VERSION 5.7 ;
  NOWIREEXTENSIONATPIN ON ;
  DIVIDERCHAR "/" ;
  BUSBITCHARS "[]" ;
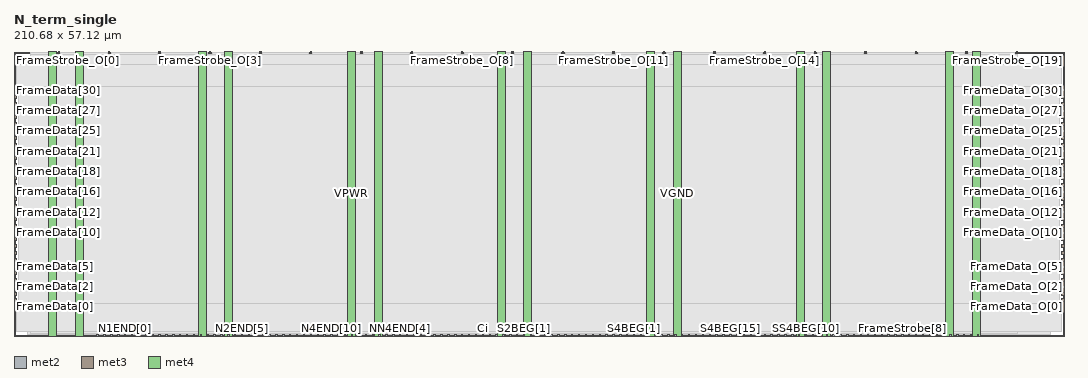
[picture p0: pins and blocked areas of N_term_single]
MACRO N_term_single
  CLASS BLOCK ;
  FOREIGN N_term_single ;
  ORIGIN 0.000 0.000 ;
  SIZE 210.680 BY 57.120 ;
  PIN Ci
    DIRECTION INPUT ;
    USE SIGNAL ;
    PORT
      LAYER met2 ;
        RECT 93.930 0.000 94.210 0.280 ;
    END
  END Ci
  PIN FrameData[0]
    DIRECTION INPUT ;
    USE SIGNAL ;
    ANTENNAGATEAREA 0.159000 ;
    PORT
      LAYER met3 ;
        RECT 0.000 6.840 0.600 7.440 ;
    END
  END FrameData[0]
  PIN FrameData[10]
    DIRECTION INPUT ;
    USE SIGNAL ;
    ANTENNAGATEAREA 0.593700 ;
    ANTENNADIFFAREA 0.434700 ;
    PORT
      LAYER met3 ;
        RECT 0.000 20.440 0.600 21.040 ;
    END
  END FrameData[10]
  PIN FrameData[11]
    DIRECTION INPUT ;
    USE SIGNAL ;
    ANTENNAGATEAREA 0.593700 ;
    ANTENNADIFFAREA 0.434700 ;
    PORT
      LAYER met3 ;
        RECT 0.000 21.800 0.600 22.400 ;
    END
  END FrameData[11]
  PIN FrameData[12]
    DIRECTION INPUT ;
    USE SIGNAL ;
    ANTENNAGATEAREA 0.593700 ;
    ANTENNADIFFAREA 0.434700 ;
    PORT
      LAYER met3 ;
        RECT 0.000 23.160 0.600 23.760 ;
    END
  END FrameData[12]
  PIN FrameData[13]
    DIRECTION INPUT ;
    USE SIGNAL ;
    ANTENNAGATEAREA 0.593700 ;
    ANTENNADIFFAREA 0.434700 ;
    PORT
      LAYER met3 ;
        RECT 0.000 24.520 0.600 25.120 ;
    END
  END FrameData[13]
  PIN FrameData[14]
    DIRECTION INPUT ;
    USE SIGNAL ;
    ANTENNAGATEAREA 0.593700 ;
    ANTENNADIFFAREA 0.434700 ;
    PORT
      LAYER met3 ;
        RECT 0.000 25.880 0.600 26.480 ;
    END
  END FrameData[14]
  PIN FrameData[15]
    DIRECTION INPUT ;
    USE SIGNAL ;
    ANTENNAGATEAREA 0.159000 ;
    PORT
      LAYER met3 ;
        RECT 0.000 27.240 0.600 27.840 ;
    END
  END FrameData[15]
  PIN FrameData[16]
    DIRECTION INPUT ;
    USE SIGNAL ;
    ANTENNAGATEAREA 0.593700 ;
    ANTENNADIFFAREA 0.434700 ;
    PORT
      LAYER met3 ;
        RECT 0.000 28.600 0.600 29.200 ;
    END
  END FrameData[16]
  PIN FrameData[17]
    DIRECTION INPUT ;
    USE SIGNAL ;
    ANTENNAGATEAREA 0.593700 ;
    ANTENNADIFFAREA 0.434700 ;
    PORT
      LAYER met3 ;
        RECT 0.000 29.960 0.600 30.560 ;
    END
  END FrameData[17]
  PIN FrameData[18]
    DIRECTION INPUT ;
    USE SIGNAL ;
    ANTENNAGATEAREA 0.593700 ;
    ANTENNADIFFAREA 0.434700 ;
    PORT
      LAYER met3 ;
        RECT 0.000 31.320 0.600 31.920 ;
    END
  END FrameData[18]
  PIN FrameData[19]
    DIRECTION INPUT ;
    USE SIGNAL ;
    ANTENNAGATEAREA 0.593700 ;
    ANTENNADIFFAREA 0.434700 ;
    PORT
      LAYER met3 ;
        RECT 0.000 32.680 0.600 33.280 ;
    END
  END FrameData[19]
  PIN FrameData[1]
    DIRECTION INPUT ;
    USE SIGNAL ;
    ANTENNAGATEAREA 0.593700 ;
    ANTENNADIFFAREA 0.434700 ;
    PORT
      LAYER met3 ;
        RECT 0.000 8.200 0.600 8.800 ;
    END
  END FrameData[1]
  PIN FrameData[20]
    DIRECTION INPUT ;
    USE SIGNAL ;
    ANTENNAGATEAREA 0.593700 ;
    ANTENNADIFFAREA 0.434700 ;
    PORT
      LAYER met3 ;
        RECT 0.000 34.040 0.600 34.640 ;
    END
  END FrameData[20]
  PIN FrameData[21]
    DIRECTION INPUT ;
    USE SIGNAL ;
    ANTENNAGATEAREA 0.593700 ;
    ANTENNADIFFAREA 0.434700 ;
    PORT
      LAYER met3 ;
        RECT 0.000 35.400 0.600 36.000 ;
    END
  END FrameData[21]
  PIN FrameData[22]
    DIRECTION INPUT ;
    USE SIGNAL ;
    ANTENNAGATEAREA 0.159000 ;
    PORT
      LAYER met3 ;
        RECT 0.000 36.760 0.600 37.360 ;
    END
  END FrameData[22]
  PIN FrameData[23]
    DIRECTION INPUT ;
    USE SIGNAL ;
    ANTENNAGATEAREA 0.593700 ;
    ANTENNADIFFAREA 0.434700 ;
    PORT
      LAYER met3 ;
        RECT 0.000 38.120 0.600 38.720 ;
    END
  END FrameData[23]
  PIN FrameData[24]
    DIRECTION INPUT ;
    USE SIGNAL ;
    ANTENNAGATEAREA 0.593700 ;
    ANTENNADIFFAREA 0.434700 ;
    PORT
      LAYER met3 ;
        RECT 0.000 39.480 0.600 40.080 ;
    END
  END FrameData[24]
  PIN FrameData[25]
    DIRECTION INPUT ;
    USE SIGNAL ;
    ANTENNAGATEAREA 0.593700 ;
    ANTENNADIFFAREA 0.434700 ;
    PORT
      LAYER met3 ;
        RECT 0.000 40.840 0.600 41.440 ;
    END
  END FrameData[25]
  PIN FrameData[26]
    DIRECTION INPUT ;
    USE SIGNAL ;
    ANTENNAGATEAREA 0.593700 ;
    ANTENNADIFFAREA 0.434700 ;
    PORT
      LAYER met3 ;
        RECT 0.000 42.200 0.600 42.800 ;
    END
  END FrameData[26]
  PIN FrameData[27]
    DIRECTION INPUT ;
    USE SIGNAL ;
    ANTENNAGATEAREA 0.593700 ;
    ANTENNADIFFAREA 0.434700 ;
    PORT
      LAYER met3 ;
        RECT 0.000 43.560 0.600 44.160 ;
    END
  END FrameData[27]
  PIN FrameData[28]
    DIRECTION INPUT ;
    USE SIGNAL ;
    ANTENNAGATEAREA 0.593700 ;
    ANTENNADIFFAREA 0.434700 ;
    PORT
      LAYER met3 ;
        RECT 0.000 44.920 0.600 45.520 ;
    END
  END FrameData[28]
  PIN FrameData[29]
    DIRECTION INPUT ;
    USE SIGNAL ;
    ANTENNAGATEAREA 0.593700 ;
    ANTENNADIFFAREA 0.434700 ;
    PORT
      LAYER met3 ;
        RECT 0.000 46.280 0.600 46.880 ;
    END
  END FrameData[29]
  PIN FrameData[2]
    DIRECTION INPUT ;
    USE SIGNAL ;
    ANTENNAGATEAREA 0.593700 ;
    ANTENNADIFFAREA 0.434700 ;
    PORT
      LAYER met3 ;
        RECT 0.000 9.560 0.600 10.160 ;
    END
  END FrameData[2]
  PIN FrameData[30]
    DIRECTION INPUT ;
    USE SIGNAL ;
    ANTENNAGATEAREA 0.593700 ;
    ANTENNADIFFAREA 0.434700 ;
    PORT
      LAYER met3 ;
        RECT 0.000 47.640 0.600 48.240 ;
    END
  END FrameData[30]
  PIN FrameData[31]
    DIRECTION INPUT ;
    USE SIGNAL ;
    ANTENNAGATEAREA 0.593700 ;
    ANTENNADIFFAREA 0.434700 ;
    PORT
      LAYER met3 ;
        RECT 0.000 49.000 0.600 49.600 ;
    END
  END FrameData[31]
  PIN FrameData[3]
    DIRECTION INPUT ;
    USE SIGNAL ;
    ANTENNAGATEAREA 0.159000 ;
    PORT
      LAYER met3 ;
        RECT 0.000 10.920 0.600 11.520 ;
    END
  END FrameData[3]
  PIN FrameData[4]
    DIRECTION INPUT ;
    USE SIGNAL ;
    ANTENNAGATEAREA 0.593700 ;
    ANTENNADIFFAREA 0.434700 ;
    PORT
      LAYER met3 ;
        RECT 0.000 12.280 0.600 12.880 ;
    END
  END FrameData[4]
  PIN FrameData[5]
    DIRECTION INPUT ;
    USE SIGNAL ;
    ANTENNAGATEAREA 0.593700 ;
    ANTENNADIFFAREA 0.434700 ;
    PORT
      LAYER met3 ;
        RECT 0.000 13.640 0.600 14.240 ;
    END
  END FrameData[5]
  PIN FrameData[6]
    DIRECTION INPUT ;
    USE SIGNAL ;
    ANTENNAGATEAREA 0.593700 ;
    ANTENNADIFFAREA 0.434700 ;
    PORT
      LAYER met3 ;
        RECT 0.000 15.000 0.600 15.600 ;
    END
  END FrameData[6]
  PIN FrameData[7]
    DIRECTION INPUT ;
    USE SIGNAL ;
    ANTENNAGATEAREA 0.593700 ;
    ANTENNADIFFAREA 0.434700 ;
    PORT
      LAYER met3 ;
        RECT 0.000 16.360 0.600 16.960 ;
    END
  END FrameData[7]
  PIN FrameData[8]
    DIRECTION INPUT ;
    USE SIGNAL ;
    ANTENNAGATEAREA 0.593700 ;
    ANTENNADIFFAREA 0.434700 ;
    PORT
      LAYER met3 ;
        RECT 0.000 17.720 0.600 18.320 ;
    END
  END FrameData[8]
  PIN FrameData[9]
    DIRECTION INPUT ;
    USE SIGNAL ;
    ANTENNAGATEAREA 0.593700 ;
    ANTENNADIFFAREA 0.434700 ;
    PORT
      LAYER met3 ;
        RECT 0.000 19.080 0.600 19.680 ;
    END
  END FrameData[9]
  PIN FrameData_O[0]
    DIRECTION OUTPUT ;
    USE SIGNAL ;
    ANTENNADIFFAREA 0.702900 ;
    PORT
      LAYER met3 ;
        RECT 210.080 6.840 210.680 7.440 ;
    END
  END FrameData_O[0]
  PIN FrameData_O[10]
    DIRECTION OUTPUT ;
    USE SIGNAL ;
    ANTENNADIFFAREA 0.702900 ;
    PORT
      LAYER met3 ;
        RECT 210.080 20.440 210.680 21.040 ;
    END
  END FrameData_O[10]
  PIN FrameData_O[11]
    DIRECTION OUTPUT ;
    USE SIGNAL ;
    ANTENNADIFFAREA 0.702900 ;
    PORT
      LAYER met3 ;
        RECT 210.080 21.800 210.680 22.400 ;
    END
  END FrameData_O[11]
  PIN FrameData_O[12]
    DIRECTION OUTPUT ;
    USE SIGNAL ;
    ANTENNADIFFAREA 0.702900 ;
    PORT
      LAYER met3 ;
        RECT 210.080 23.160 210.680 23.760 ;
    END
  END FrameData_O[12]
  PIN FrameData_O[13]
    DIRECTION OUTPUT ;
    USE SIGNAL ;
    ANTENNADIFFAREA 0.702900 ;
    PORT
      LAYER met3 ;
        RECT 210.080 24.520 210.680 25.120 ;
    END
  END FrameData_O[13]
  PIN FrameData_O[14]
    DIRECTION OUTPUT ;
    USE SIGNAL ;
    ANTENNADIFFAREA 0.702900 ;
    PORT
      LAYER met3 ;
        RECT 210.080 25.880 210.680 26.480 ;
    END
  END FrameData_O[14]
  PIN FrameData_O[15]
    DIRECTION OUTPUT ;
    USE SIGNAL ;
    ANTENNADIFFAREA 0.702900 ;
    PORT
      LAYER met3 ;
        RECT 210.080 27.240 210.680 27.840 ;
    END
  END FrameData_O[15]
  PIN FrameData_O[16]
    DIRECTION OUTPUT ;
    USE SIGNAL ;
    ANTENNADIFFAREA 0.702900 ;
    PORT
      LAYER met3 ;
        RECT 210.080 28.600 210.680 29.200 ;
    END
  END FrameData_O[16]
  PIN FrameData_O[17]
    DIRECTION OUTPUT ;
    USE SIGNAL ;
    ANTENNADIFFAREA 0.702900 ;
    PORT
      LAYER met3 ;
        RECT 210.080 29.960 210.680 30.560 ;
    END
  END FrameData_O[17]
  PIN FrameData_O[18]
    DIRECTION OUTPUT ;
    USE SIGNAL ;
    ANTENNADIFFAREA 0.702900 ;
    PORT
      LAYER met3 ;
        RECT 210.080 31.320 210.680 31.920 ;
    END
  END FrameData_O[18]
  PIN FrameData_O[19]
    DIRECTION OUTPUT ;
    USE SIGNAL ;
    ANTENNADIFFAREA 0.702900 ;
    PORT
      LAYER met3 ;
        RECT 210.080 32.680 210.680 33.280 ;
    END
  END FrameData_O[19]
  PIN FrameData_O[1]
    DIRECTION OUTPUT ;
    USE SIGNAL ;
    ANTENNADIFFAREA 0.702900 ;
    PORT
      LAYER met3 ;
        RECT 210.080 8.200 210.680 8.800 ;
    END
  END FrameData_O[1]
  PIN FrameData_O[20]
    DIRECTION OUTPUT ;
    USE SIGNAL ;
    ANTENNADIFFAREA 0.702900 ;
    PORT
      LAYER met3 ;
        RECT 210.080 34.040 210.680 34.640 ;
    END
  END FrameData_O[20]
  PIN FrameData_O[21]
    DIRECTION OUTPUT ;
    USE SIGNAL ;
    ANTENNADIFFAREA 0.702900 ;
    PORT
      LAYER met3 ;
        RECT 210.080 35.400 210.680 36.000 ;
    END
  END FrameData_O[21]
  PIN FrameData_O[22]
    DIRECTION OUTPUT ;
    USE SIGNAL ;
    ANTENNADIFFAREA 0.702900 ;
    PORT
      LAYER met3 ;
        RECT 210.080 36.760 210.680 37.360 ;
    END
  END FrameData_O[22]
  PIN FrameData_O[23]
    DIRECTION OUTPUT ;
    USE SIGNAL ;
    ANTENNADIFFAREA 0.702900 ;
    PORT
      LAYER met3 ;
        RECT 210.080 38.120 210.680 38.720 ;
    END
  END FrameData_O[23]
  PIN FrameData_O[24]
    DIRECTION OUTPUT ;
    USE SIGNAL ;
    ANTENNADIFFAREA 0.702900 ;
    PORT
      LAYER met3 ;
        RECT 210.080 39.480 210.680 40.080 ;
    END
  END FrameData_O[24]
  PIN FrameData_O[25]
    DIRECTION OUTPUT ;
    USE SIGNAL ;
    ANTENNADIFFAREA 0.702900 ;
    PORT
      LAYER met3 ;
        RECT 210.080 40.840 210.680 41.440 ;
    END
  END FrameData_O[25]
  PIN FrameData_O[26]
    DIRECTION OUTPUT ;
    USE SIGNAL ;
    ANTENNADIFFAREA 0.702900 ;
    PORT
      LAYER met3 ;
        RECT 210.080 42.200 210.680 42.800 ;
    END
  END FrameData_O[26]
  PIN FrameData_O[27]
    DIRECTION OUTPUT ;
    USE SIGNAL ;
    ANTENNADIFFAREA 0.702900 ;
    PORT
      LAYER met3 ;
        RECT 210.080 43.560 210.680 44.160 ;
    END
  END FrameData_O[27]
  PIN FrameData_O[28]
    DIRECTION OUTPUT ;
    USE SIGNAL ;
    ANTENNADIFFAREA 0.702900 ;
    PORT
      LAYER met3 ;
        RECT 210.080 44.920 210.680 45.520 ;
    END
  END FrameData_O[28]
  PIN FrameData_O[29]
    DIRECTION OUTPUT ;
    USE SIGNAL ;
    ANTENNADIFFAREA 0.702900 ;
    PORT
      LAYER met3 ;
        RECT 210.080 46.280 210.680 46.880 ;
    END
  END FrameData_O[29]
  PIN FrameData_O[2]
    DIRECTION OUTPUT ;
    USE SIGNAL ;
    ANTENNADIFFAREA 0.702900 ;
    PORT
      LAYER met3 ;
        RECT 210.080 9.560 210.680 10.160 ;
    END
  END FrameData_O[2]
  PIN FrameData_O[30]
    DIRECTION OUTPUT ;
    USE SIGNAL ;
    ANTENNADIFFAREA 0.702900 ;
    PORT
      LAYER met3 ;
        RECT 210.080 47.640 210.680 48.240 ;
    END
  END FrameData_O[30]
  PIN FrameData_O[31]
    DIRECTION OUTPUT ;
    USE SIGNAL ;
    ANTENNADIFFAREA 0.702900 ;
    PORT
      LAYER met3 ;
        RECT 210.080 49.000 210.680 49.600 ;
    END
  END FrameData_O[31]
  PIN FrameData_O[3]
    DIRECTION OUTPUT ;
    USE SIGNAL ;
    ANTENNADIFFAREA 0.702900 ;
    PORT
      LAYER met3 ;
        RECT 210.080 10.920 210.680 11.520 ;
    END
  END FrameData_O[3]
  PIN FrameData_O[4]
    DIRECTION OUTPUT ;
    USE SIGNAL ;
    ANTENNADIFFAREA 0.702900 ;
    PORT
      LAYER met3 ;
        RECT 210.080 12.280 210.680 12.880 ;
    END
  END FrameData_O[4]
  PIN FrameData_O[5]
    DIRECTION OUTPUT ;
    USE SIGNAL ;
    ANTENNADIFFAREA 0.702900 ;
    PORT
      LAYER met3 ;
        RECT 210.080 13.640 210.680 14.240 ;
    END
  END FrameData_O[5]
  PIN FrameData_O[6]
    DIRECTION OUTPUT ;
    USE SIGNAL ;
    ANTENNADIFFAREA 0.702900 ;
    PORT
      LAYER met3 ;
        RECT 210.080 15.000 210.680 15.600 ;
    END
  END FrameData_O[6]
  PIN FrameData_O[7]
    DIRECTION OUTPUT ;
    USE SIGNAL ;
    ANTENNADIFFAREA 0.702900 ;
    PORT
      LAYER met3 ;
        RECT 210.080 16.360 210.680 16.960 ;
    END
  END FrameData_O[7]
  PIN FrameData_O[8]
    DIRECTION OUTPUT ;
    USE SIGNAL ;
    ANTENNADIFFAREA 0.702900 ;
    PORT
      LAYER met3 ;
        RECT 210.080 17.720 210.680 18.320 ;
    END
  END FrameData_O[8]
  PIN FrameData_O[9]
    DIRECTION OUTPUT ;
    USE SIGNAL ;
    ANTENNADIFFAREA 0.702900 ;
    PORT
      LAYER met3 ;
        RECT 210.080 19.080 210.680 19.680 ;
    END
  END FrameData_O[9]
  PIN FrameStrobe[0]
    DIRECTION INPUT ;
    USE SIGNAL ;
    ANTENNAGATEAREA 0.159000 ;
    PORT
      LAYER met2 ;
        RECT 167.070 0.000 167.350 0.280 ;
    END
  END FrameStrobe[0]
  PIN FrameStrobe[10]
    DIRECTION INPUT ;
    USE SIGNAL ;
    ANTENNAGATEAREA 0.593700 ;
    ANTENNADIFFAREA 0.434700 ;
    PORT
      LAYER met2 ;
        RECT 180.870 0.000 181.150 0.280 ;
    END
  END FrameStrobe[10]
  PIN FrameStrobe[11]
    DIRECTION INPUT ;
    USE SIGNAL ;
    ANTENNAGATEAREA 0.159000 ;
    PORT
      LAYER met2 ;
        RECT 182.250 0.000 182.530 0.280 ;
    END
  END FrameStrobe[11]
  PIN FrameStrobe[12]
    DIRECTION INPUT ;
    USE SIGNAL ;
    ANTENNAGATEAREA 0.159000 ;
    PORT
      LAYER met2 ;
        RECT 183.630 0.000 183.910 0.280 ;
    END
  END FrameStrobe[12]
  PIN FrameStrobe[13]
    DIRECTION INPUT ;
    USE SIGNAL ;
    ANTENNAGATEAREA 0.159000 ;
    PORT
      LAYER met2 ;
        RECT 185.010 0.000 185.290 0.280 ;
    END
  END FrameStrobe[13]
  PIN FrameStrobe[14]
    DIRECTION INPUT ;
    USE SIGNAL ;
    ANTENNAGATEAREA 0.159000 ;
    PORT
      LAYER met2 ;
        RECT 186.390 0.000 186.670 0.280 ;
    END
  END FrameStrobe[14]
  PIN FrameStrobe[15]
    DIRECTION INPUT ;
    USE SIGNAL ;
    ANTENNAGATEAREA 0.159000 ;
    PORT
      LAYER met2 ;
        RECT 187.770 0.000 188.050 0.280 ;
    END
  END FrameStrobe[15]
  PIN FrameStrobe[16]
    DIRECTION INPUT ;
    USE SIGNAL ;
    ANTENNAGATEAREA 0.159000 ;
    PORT
      LAYER met2 ;
        RECT 189.150 0.000 189.430 0.280 ;
    END
  END FrameStrobe[16]
  PIN FrameStrobe[17]
    DIRECTION INPUT ;
    USE SIGNAL ;
    ANTENNAGATEAREA 0.159000 ;
    PORT
      LAYER met2 ;
        RECT 190.530 0.000 190.810 0.280 ;
    END
  END FrameStrobe[17]
  PIN FrameStrobe[18]
    DIRECTION INPUT ;
    USE SIGNAL ;
    ANTENNAGATEAREA 0.159000 ;
    PORT
      LAYER met2 ;
        RECT 191.910 0.000 192.190 0.280 ;
    END
  END FrameStrobe[18]
  PIN FrameStrobe[19]
    DIRECTION INPUT ;
    USE SIGNAL ;
    ANTENNAGATEAREA 0.159000 ;
    PORT
      LAYER met2 ;
        RECT 193.290 0.000 193.570 0.280 ;
    END
  END FrameStrobe[19]
  PIN FrameStrobe[1]
    DIRECTION INPUT ;
    USE SIGNAL ;
    ANTENNAGATEAREA 0.159000 ;
    PORT
      LAYER met2 ;
        RECT 168.450 0.000 168.730 0.280 ;
    END
  END FrameStrobe[1]
  PIN FrameStrobe[2]
    DIRECTION INPUT ;
    USE SIGNAL ;
    ANTENNAGATEAREA 0.159000 ;
    PORT
      LAYER met2 ;
        RECT 169.830 0.000 170.110 0.280 ;
    END
  END FrameStrobe[2]
  PIN FrameStrobe[3]
    DIRECTION INPUT ;
    USE SIGNAL ;
    ANTENNAGATEAREA 0.593700 ;
    ANTENNADIFFAREA 0.434700 ;
    PORT
      LAYER met2 ;
        RECT 171.210 0.000 171.490 0.280 ;
    END
  END FrameStrobe[3]
  PIN FrameStrobe[4]
    DIRECTION INPUT ;
    USE SIGNAL ;
    ANTENNAGATEAREA 0.159000 ;
    PORT
      LAYER met2 ;
        RECT 172.590 0.000 172.870 0.280 ;
    END
  END FrameStrobe[4]
  PIN FrameStrobe[5]
    DIRECTION INPUT ;
    USE SIGNAL ;
    ANTENNAGATEAREA 0.593700 ;
    ANTENNADIFFAREA 0.434700 ;
    PORT
      LAYER met2 ;
        RECT 173.970 0.000 174.250 0.280 ;
    END
  END FrameStrobe[5]
  PIN FrameStrobe[6]
    DIRECTION INPUT ;
    USE SIGNAL ;
    ANTENNAGATEAREA 0.593700 ;
    ANTENNADIFFAREA 0.434700 ;
    PORT
      LAYER met2 ;
        RECT 175.350 0.000 175.630 0.280 ;
    END
  END FrameStrobe[6]
  PIN FrameStrobe[7]
    DIRECTION INPUT ;
    USE SIGNAL ;
    ANTENNAGATEAREA 0.159000 ;
    PORT
      LAYER met2 ;
        RECT 176.730 0.000 177.010 0.280 ;
    END
  END FrameStrobe[7]
  PIN FrameStrobe[8]
    DIRECTION INPUT ;
    USE SIGNAL ;
    ANTENNAGATEAREA 0.159000 ;
    PORT
      LAYER met2 ;
        RECT 178.110 0.000 178.390 0.280 ;
    END
  END FrameStrobe[8]
  PIN FrameStrobe[9]
    DIRECTION INPUT ;
    USE SIGNAL ;
    ANTENNAGATEAREA 0.593700 ;
    ANTENNADIFFAREA 0.434700 ;
    PORT
      LAYER met2 ;
        RECT 179.490 0.000 179.770 0.280 ;
    END
  END FrameStrobe[9]
  PIN FrameStrobe_O[0]
    DIRECTION OUTPUT ;
    USE SIGNAL ;
    ANTENNADIFFAREA 0.702900 ;
    PORT
      LAYER met2 ;
        RECT 8.830 56.840 9.110 57.120 ;
    END
  END FrameStrobe_O[0]
  PIN FrameStrobe_O[10]
    DIRECTION OUTPUT ;
    USE SIGNAL ;
    ANTENNADIFFAREA 0.702900 ;
    PORT
      LAYER met2 ;
        RECT 110.030 56.840 110.310 57.120 ;
    END
  END FrameStrobe_O[10]
  PIN FrameStrobe_O[11]
    DIRECTION OUTPUT ;
    USE SIGNAL ;
    ANTENNADIFFAREA 0.702900 ;
    PORT
      LAYER met2 ;
        RECT 120.150 56.840 120.430 57.120 ;
    END
  END FrameStrobe_O[11]
  PIN FrameStrobe_O[12]
    DIRECTION OUTPUT ;
    USE SIGNAL ;
    ANTENNADIFFAREA 0.702900 ;
    PORT
      LAYER met2 ;
        RECT 130.270 56.840 130.550 57.120 ;
    END
  END FrameStrobe_O[12]
  PIN FrameStrobe_O[13]
    DIRECTION OUTPUT ;
    USE SIGNAL ;
    ANTENNADIFFAREA 0.702900 ;
    PORT
      LAYER met2 ;
        RECT 140.390 56.840 140.670 57.120 ;
    END
  END FrameStrobe_O[13]
  PIN FrameStrobe_O[14]
    DIRECTION OUTPUT ;
    USE SIGNAL ;
    ANTENNADIFFAREA 0.702900 ;
    PORT
      LAYER met2 ;
        RECT 150.510 56.840 150.790 57.120 ;
    END
  END FrameStrobe_O[14]
  PIN FrameStrobe_O[15]
    DIRECTION OUTPUT ;
    USE SIGNAL ;
    ANTENNADIFFAREA 0.702900 ;
    PORT
      LAYER met2 ;
        RECT 160.630 56.840 160.910 57.120 ;
    END
  END FrameStrobe_O[15]
  PIN FrameStrobe_O[16]
    DIRECTION OUTPUT ;
    USE SIGNAL ;
    ANTENNADIFFAREA 0.702900 ;
    PORT
      LAYER met2 ;
        RECT 170.750 56.840 171.030 57.120 ;
    END
  END FrameStrobe_O[16]
  PIN FrameStrobe_O[17]
    DIRECTION OUTPUT ;
    USE SIGNAL ;
    ANTENNADIFFAREA 0.702900 ;
    PORT
      LAYER met2 ;
        RECT 180.870 56.840 181.150 57.120 ;
    END
  END FrameStrobe_O[17]
  PIN FrameStrobe_O[18]
    DIRECTION OUTPUT ;
    USE SIGNAL ;
    ANTENNADIFFAREA 0.702900 ;
    PORT
      LAYER met2 ;
        RECT 190.990 56.840 191.270 57.120 ;
    END
  END FrameStrobe_O[18]
  PIN FrameStrobe_O[19]
    DIRECTION OUTPUT ;
    USE SIGNAL ;
    ANTENNADIFFAREA 0.702900 ;
    PORT
      LAYER met2 ;
        RECT 201.110 56.840 201.390 57.120 ;
    END
  END FrameStrobe_O[19]
  PIN FrameStrobe_O[1]
    DIRECTION OUTPUT ;
    USE SIGNAL ;
    ANTENNADIFFAREA 0.702900 ;
    PORT
      LAYER met2 ;
        RECT 18.950 56.840 19.230 57.120 ;
    END
  END FrameStrobe_O[1]
  PIN FrameStrobe_O[2]
    DIRECTION OUTPUT ;
    USE SIGNAL ;
    ANTENNADIFFAREA 0.702900 ;
    PORT
      LAYER met2 ;
        RECT 29.070 56.840 29.350 57.120 ;
    END
  END FrameStrobe_O[2]
  PIN FrameStrobe_O[3]
    DIRECTION OUTPUT ;
    USE SIGNAL ;
    ANTENNADIFFAREA 0.702900 ;
    PORT
      LAYER met2 ;
        RECT 39.190 56.840 39.470 57.120 ;
    END
  END FrameStrobe_O[3]
  PIN FrameStrobe_O[4]
    DIRECTION OUTPUT ;
    USE SIGNAL ;
    ANTENNADIFFAREA 0.702900 ;
    PORT
      LAYER met2 ;
        RECT 49.310 56.840 49.590 57.120 ;
    END
  END FrameStrobe_O[4]
  PIN FrameStrobe_O[5]
    DIRECTION OUTPUT ;
    USE SIGNAL ;
    ANTENNADIFFAREA 0.702900 ;
    PORT
      LAYER met2 ;
        RECT 59.430 56.840 59.710 57.120 ;
    END
  END FrameStrobe_O[5]
  PIN FrameStrobe_O[6]
    DIRECTION OUTPUT ;
    USE SIGNAL ;
    ANTENNADIFFAREA 0.702900 ;
    PORT
      LAYER met2 ;
        RECT 69.550 56.840 69.830 57.120 ;
    END
  END FrameStrobe_O[6]
  PIN FrameStrobe_O[7]
    DIRECTION OUTPUT ;
    USE SIGNAL ;
    ANTENNADIFFAREA 0.702900 ;
    PORT
      LAYER met2 ;
        RECT 79.670 56.840 79.950 57.120 ;
    END
  END FrameStrobe_O[7]
  PIN FrameStrobe_O[8]
    DIRECTION OUTPUT ;
    USE SIGNAL ;
    ANTENNADIFFAREA 0.702900 ;
    PORT
      LAYER met2 ;
        RECT 89.790 56.840 90.070 57.120 ;
    END
  END FrameStrobe_O[8]
  PIN FrameStrobe_O[9]
    DIRECTION OUTPUT ;
    USE SIGNAL ;
    ANTENNADIFFAREA 0.702900 ;
    PORT
      LAYER met2 ;
        RECT 99.910 56.840 100.190 57.120 ;
    END
  END FrameStrobe_O[9]
  PIN N1END[0]
    DIRECTION INPUT ;
    USE SIGNAL ;
    ANTENNAGATEAREA 0.159000 ;
    PORT
      LAYER met2 ;
        RECT 22.170 0.000 22.450 0.280 ;
    END
  END N1END[0]
  PIN N1END[1]
    DIRECTION INPUT ;
    USE SIGNAL ;
    ANTENNAGATEAREA 0.159000 ;
    PORT
      LAYER met2 ;
        RECT 23.550 0.000 23.830 0.280 ;
    END
  END N1END[1]
  PIN N1END[2]
    DIRECTION INPUT ;
    USE SIGNAL ;
    ANTENNAGATEAREA 0.159000 ;
    PORT
      LAYER met2 ;
        RECT 24.930 0.000 25.210 0.280 ;
    END
  END N1END[2]
  PIN N1END[3]
    DIRECTION INPUT ;
    USE SIGNAL ;
    ANTENNAGATEAREA 0.159000 ;
    PORT
      LAYER met2 ;
        RECT 26.310 0.000 26.590 0.280 ;
    END
  END N1END[3]
  PIN N2END[0]
    DIRECTION INPUT ;
    USE SIGNAL ;
    ANTENNAGATEAREA 0.159000 ;
    PORT
      LAYER met2 ;
        RECT 38.730 0.000 39.010 0.280 ;
    END
  END N2END[0]
  PIN N2END[1]
    DIRECTION INPUT ;
    USE SIGNAL ;
    ANTENNAGATEAREA 0.159000 ;
    PORT
      LAYER met2 ;
        RECT 40.110 0.000 40.390 0.280 ;
    END
  END N2END[1]
  PIN N2END[2]
    DIRECTION INPUT ;
    USE SIGNAL ;
    ANTENNAGATEAREA 0.159000 ;
    PORT
      LAYER met2 ;
        RECT 41.490 0.000 41.770 0.280 ;
    END
  END N2END[2]
  PIN N2END[3]
    DIRECTION INPUT ;
    USE SIGNAL ;
    ANTENNAGATEAREA 0.159000 ;
    PORT
      LAYER met2 ;
        RECT 42.870 0.000 43.150 0.280 ;
    END
  END N2END[3]
  PIN N2END[4]
    DIRECTION INPUT ;
    USE SIGNAL ;
    ANTENNAGATEAREA 0.159000 ;
    PORT
      LAYER met2 ;
        RECT 44.250 0.000 44.530 0.280 ;
    END
  END N2END[4]
  PIN N2END[5]
    DIRECTION INPUT ;
    USE SIGNAL ;
    ANTENNAGATEAREA 0.159000 ;
    PORT
      LAYER met2 ;
        RECT 45.630 0.000 45.910 0.280 ;
    END
  END N2END[5]
  PIN N2END[6]
    DIRECTION INPUT ;
    USE SIGNAL ;
    ANTENNAGATEAREA 0.159000 ;
    PORT
      LAYER met2 ;
        RECT 47.010 0.000 47.290 0.280 ;
    END
  END N2END[6]
  PIN N2END[7]
    DIRECTION INPUT ;
    USE SIGNAL ;
    ANTENNAGATEAREA 0.159000 ;
    PORT
      LAYER met2 ;
        RECT 48.390 0.000 48.670 0.280 ;
    END
  END N2END[7]
  PIN N2MID[0]
    DIRECTION INPUT ;
    USE SIGNAL ;
    ANTENNAGATEAREA 0.159000 ;
    PORT
      LAYER met2 ;
        RECT 27.690 0.000 27.970 0.280 ;
    END
  END N2MID[0]
  PIN N2MID[1]
    DIRECTION INPUT ;
    USE SIGNAL ;
    ANTENNAGATEAREA 0.159000 ;
    PORT
      LAYER met2 ;
        RECT 29.070 0.000 29.350 0.280 ;
    END
  END N2MID[1]
  PIN N2MID[2]
    DIRECTION INPUT ;
    USE SIGNAL ;
    ANTENNAGATEAREA 0.159000 ;
    PORT
      LAYER met2 ;
        RECT 30.450 0.000 30.730 0.280 ;
    END
  END N2MID[2]
  PIN N2MID[3]
    DIRECTION INPUT ;
    USE SIGNAL ;
    ANTENNAGATEAREA 0.159000 ;
    PORT
      LAYER met2 ;
        RECT 31.830 0.000 32.110 0.280 ;
    END
  END N2MID[3]
  PIN N2MID[4]
    DIRECTION INPUT ;
    USE SIGNAL ;
    ANTENNAGATEAREA 0.159000 ;
    PORT
      LAYER met2 ;
        RECT 33.210 0.000 33.490 0.280 ;
    END
  END N2MID[4]
  PIN N2MID[5]
    DIRECTION INPUT ;
    USE SIGNAL ;
    ANTENNAGATEAREA 0.159000 ;
    PORT
      LAYER met2 ;
        RECT 34.590 0.000 34.870 0.280 ;
    END
  END N2MID[5]
  PIN N2MID[6]
    DIRECTION INPUT ;
    USE SIGNAL ;
    ANTENNAGATEAREA 0.159000 ;
    PORT
      LAYER met2 ;
        RECT 35.970 0.000 36.250 0.280 ;
    END
  END N2MID[6]
  PIN N2MID[7]
    DIRECTION INPUT ;
    USE SIGNAL ;
    ANTENNAGATEAREA 0.159000 ;
    PORT
      LAYER met2 ;
        RECT 37.350 0.000 37.630 0.280 ;
    END
  END N2MID[7]
  PIN N4END[0]
    DIRECTION INPUT ;
    USE SIGNAL ;
    ANTENNAGATEAREA 0.159000 ;
    PORT
      LAYER met2 ;
        RECT 49.770 0.000 50.050 0.280 ;
    END
  END N4END[0]
  PIN N4END[10]
    DIRECTION INPUT ;
    USE SIGNAL ;
    ANTENNAGATEAREA 0.159000 ;
    PORT
      LAYER met2 ;
        RECT 63.570 0.000 63.850 0.280 ;
    END
  END N4END[10]
  PIN N4END[11]
    DIRECTION INPUT ;
    USE SIGNAL ;
    ANTENNAGATEAREA 0.159000 ;
    PORT
      LAYER met2 ;
        RECT 64.950 0.000 65.230 0.280 ;
    END
  END N4END[11]
  PIN N4END[12]
    DIRECTION INPUT ;
    USE SIGNAL ;
    ANTENNAGATEAREA 0.159000 ;
    PORT
      LAYER met2 ;
        RECT 66.330 0.000 66.610 0.280 ;
    END
  END N4END[12]
  PIN N4END[13]
    DIRECTION INPUT ;
    USE SIGNAL ;
    ANTENNAGATEAREA 0.593700 ;
    ANTENNADIFFAREA 0.434700 ;
    PORT
      LAYER met2 ;
        RECT 67.710 0.000 67.990 0.280 ;
    END
  END N4END[13]
  PIN N4END[14]
    DIRECTION INPUT ;
    USE SIGNAL ;
    ANTENNAGATEAREA 0.159000 ;
    PORT
      LAYER met2 ;
        RECT 69.090 0.000 69.370 0.280 ;
    END
  END N4END[14]
  PIN N4END[15]
    DIRECTION INPUT ;
    USE SIGNAL ;
    ANTENNAGATEAREA 0.159000 ;
    PORT
      LAYER met2 ;
        RECT 70.470 0.000 70.750 0.280 ;
    END
  END N4END[15]
  PIN N4END[1]
    DIRECTION INPUT ;
    USE SIGNAL ;
    ANTENNAGATEAREA 0.159000 ;
    PORT
      LAYER met2 ;
        RECT 51.150 0.000 51.430 0.280 ;
    END
  END N4END[1]
  PIN N4END[2]
    DIRECTION INPUT ;
    USE SIGNAL ;
    ANTENNAGATEAREA 0.159000 ;
    PORT
      LAYER met2 ;
        RECT 52.530 0.000 52.810 0.280 ;
    END
  END N4END[2]
  PIN N4END[3]
    DIRECTION INPUT ;
    USE SIGNAL ;
    ANTENNAGATEAREA 0.159000 ;
    PORT
      LAYER met2 ;
        RECT 53.910 0.000 54.190 0.280 ;
    END
  END N4END[3]
  PIN N4END[4]
    DIRECTION INPUT ;
    USE SIGNAL ;
    ANTENNAGATEAREA 0.159000 ;
    PORT
      LAYER met2 ;
        RECT 55.290 0.000 55.570 0.280 ;
    END
  END N4END[4]
  PIN N4END[5]
    DIRECTION INPUT ;
    USE SIGNAL ;
    ANTENNAGATEAREA 0.159000 ;
    PORT
      LAYER met2 ;
        RECT 56.670 0.000 56.950 0.280 ;
    END
  END N4END[5]
  PIN N4END[6]
    DIRECTION INPUT ;
    USE SIGNAL ;
    ANTENNAGATEAREA 0.159000 ;
    PORT
      LAYER met2 ;
        RECT 58.050 0.000 58.330 0.280 ;
    END
  END N4END[6]
  PIN N4END[7]
    DIRECTION INPUT ;
    USE SIGNAL ;
    ANTENNAGATEAREA 0.159000 ;
    PORT
      LAYER met2 ;
        RECT 59.430 0.000 59.710 0.280 ;
    END
  END N4END[7]
  PIN N4END[8]
    DIRECTION INPUT ;
    USE SIGNAL ;
    ANTENNAGATEAREA 0.159000 ;
    PORT
      LAYER met2 ;
        RECT 60.810 0.000 61.090 0.280 ;
    END
  END N4END[8]
  PIN N4END[9]
    DIRECTION INPUT ;
    USE SIGNAL ;
    ANTENNAGATEAREA 0.159000 ;
    PORT
      LAYER met2 ;
        RECT 62.190 0.000 62.470 0.280 ;
    END
  END N4END[9]
  PIN NN4END[0]
    DIRECTION INPUT ;
    USE SIGNAL ;
    ANTENNAGATEAREA 0.159000 ;
    PORT
      LAYER met2 ;
        RECT 71.850 0.000 72.130 0.280 ;
    END
  END NN4END[0]
  PIN NN4END[10]
    DIRECTION INPUT ;
    USE SIGNAL ;
    ANTENNAGATEAREA 0.159000 ;
    PORT
      LAYER met2 ;
        RECT 85.650 0.000 85.930 0.280 ;
    END
  END NN4END[10]
  PIN NN4END[11]
    DIRECTION INPUT ;
    USE SIGNAL ;
    ANTENNAGATEAREA 0.159000 ;
    PORT
      LAYER met2 ;
        RECT 87.030 0.000 87.310 0.280 ;
    END
  END NN4END[11]
  PIN NN4END[12]
    DIRECTION INPUT ;
    USE SIGNAL ;
    ANTENNAGATEAREA 0.159000 ;
    PORT
      LAYER met2 ;
        RECT 88.410 0.000 88.690 0.280 ;
    END
  END NN4END[12]
  PIN NN4END[13]
    DIRECTION INPUT ;
    USE SIGNAL ;
    ANTENNAGATEAREA 0.159000 ;
    PORT
      LAYER met2 ;
        RECT 89.790 0.000 90.070 0.280 ;
    END
  END NN4END[13]
  PIN NN4END[14]
    DIRECTION INPUT ;
    USE SIGNAL ;
    ANTENNAGATEAREA 0.159000 ;
    PORT
      LAYER met2 ;
        RECT 91.170 0.000 91.450 0.280 ;
    END
  END NN4END[14]
  PIN NN4END[15]
    DIRECTION INPUT ;
    USE SIGNAL ;
    ANTENNAGATEAREA 0.159000 ;
    PORT
      LAYER met2 ;
        RECT 92.550 0.000 92.830 0.280 ;
    END
  END NN4END[15]
  PIN NN4END[1]
    DIRECTION INPUT ;
    USE SIGNAL ;
    ANTENNAGATEAREA 0.593700 ;
    ANTENNADIFFAREA 0.434700 ;
    PORT
      LAYER met2 ;
        RECT 73.230 0.000 73.510 0.280 ;
    END
  END NN4END[1]
  PIN NN4END[2]
    DIRECTION INPUT ;
    USE SIGNAL ;
    ANTENNAGATEAREA 0.593700 ;
    ANTENNADIFFAREA 0.434700 ;
    PORT
      LAYER met2 ;
        RECT 74.610 0.000 74.890 0.280 ;
    END
  END NN4END[2]
  PIN NN4END[3]
    DIRECTION INPUT ;
    USE SIGNAL ;
    ANTENNAGATEAREA 0.593700 ;
    ANTENNADIFFAREA 0.434700 ;
    PORT
      LAYER met2 ;
        RECT 75.990 0.000 76.270 0.280 ;
    END
  END NN4END[3]
  PIN NN4END[4]
    DIRECTION INPUT ;
    USE SIGNAL ;
    ANTENNAGATEAREA 0.593700 ;
    ANTENNADIFFAREA 0.434700 ;
    PORT
      LAYER met2 ;
        RECT 77.370 0.000 77.650 0.280 ;
    END
  END NN4END[4]
  PIN NN4END[5]
    DIRECTION INPUT ;
    USE SIGNAL ;
    ANTENNAGATEAREA 0.159000 ;
    PORT
      LAYER met2 ;
        RECT 78.750 0.000 79.030 0.280 ;
    END
  END NN4END[5]
  PIN NN4END[6]
    DIRECTION INPUT ;
    USE SIGNAL ;
    ANTENNAGATEAREA 0.593700 ;
    ANTENNADIFFAREA 0.434700 ;
    PORT
      LAYER met2 ;
        RECT 80.130 0.000 80.410 0.280 ;
    END
  END NN4END[6]
  PIN NN4END[7]
    DIRECTION INPUT ;
    USE SIGNAL ;
    ANTENNAGATEAREA 0.159000 ;
    PORT
      LAYER met2 ;
        RECT 81.510 0.000 81.790 0.280 ;
    END
  END NN4END[7]
  PIN NN4END[8]
    DIRECTION INPUT ;
    USE SIGNAL ;
    ANTENNAGATEAREA 0.159000 ;
    PORT
      LAYER met2 ;
        RECT 82.890 0.000 83.170 0.280 ;
    END
  END NN4END[8]
  PIN NN4END[9]
    DIRECTION INPUT ;
    USE SIGNAL ;
    ANTENNAGATEAREA 0.159000 ;
    PORT
      LAYER met2 ;
        RECT 84.270 0.000 84.550 0.280 ;
    END
  END NN4END[9]
  PIN N_GBUF_END[0]
    DIRECTION INPUT ;
    USE SIGNAL ;
    PORT
      LAYER met2 ;
        RECT 16.650 0.000 16.930 0.280 ;
    END
  END N_GBUF_END[0]
  PIN N_GBUF_END[1]
    DIRECTION INPUT ;
    USE SIGNAL ;
    PORT
      LAYER met2 ;
        RECT 18.030 0.000 18.310 0.280 ;
    END
  END N_GBUF_END[1]
  PIN N_GBUF_END[2]
    DIRECTION INPUT ;
    USE SIGNAL ;
    PORT
      LAYER met2 ;
        RECT 19.410 0.000 19.690 0.280 ;
    END
  END N_GBUF_END[2]
  PIN N_GBUF_END[3]
    DIRECTION INPUT ;
    USE SIGNAL ;
    PORT
      LAYER met2 ;
        RECT 20.790 0.000 21.070 0.280 ;
    END
  END N_GBUF_END[3]
  PIN S1BEG[0]
    DIRECTION OUTPUT ;
    USE SIGNAL ;
    ANTENNADIFFAREA 0.702900 ;
    PORT
      LAYER met2 ;
        RECT 95.310 0.000 95.590 0.280 ;
    END
  END S1BEG[0]
  PIN S1BEG[1]
    DIRECTION OUTPUT ;
    USE SIGNAL ;
    ANTENNADIFFAREA 0.702900 ;
    PORT
      LAYER met2 ;
        RECT 96.690 0.000 96.970 0.280 ;
    END
  END S1BEG[1]
  PIN S1BEG[2]
    DIRECTION OUTPUT ;
    USE SIGNAL ;
    ANTENNADIFFAREA 0.702900 ;
    PORT
      LAYER met2 ;
        RECT 98.070 0.000 98.350 0.280 ;
    END
  END S1BEG[2]
  PIN S1BEG[3]
    DIRECTION OUTPUT ;
    USE SIGNAL ;
    ANTENNADIFFAREA 0.702900 ;
    PORT
      LAYER met2 ;
        RECT 99.450 0.000 99.730 0.280 ;
    END
  END S1BEG[3]
  PIN S2BEG[0]
    DIRECTION OUTPUT ;
    USE SIGNAL ;
    ANTENNADIFFAREA 0.702900 ;
    PORT
      LAYER met2 ;
        RECT 100.830 0.000 101.110 0.280 ;
    END
  END S2BEG[0]
  PIN S2BEG[1]
    DIRECTION OUTPUT ;
    USE SIGNAL ;
    ANTENNADIFFAREA 0.702900 ;
    PORT
      LAYER met2 ;
        RECT 102.210 0.000 102.490 0.280 ;
    END
  END S2BEG[1]
  PIN S2BEG[2]
    DIRECTION OUTPUT ;
    USE SIGNAL ;
    ANTENNADIFFAREA 0.702900 ;
    PORT
      LAYER met2 ;
        RECT 103.590 0.000 103.870 0.280 ;
    END
  END S2BEG[2]
  PIN S2BEG[3]
    DIRECTION OUTPUT ;
    USE SIGNAL ;
    ANTENNADIFFAREA 0.702900 ;
    PORT
      LAYER met2 ;
        RECT 104.970 0.000 105.250 0.280 ;
    END
  END S2BEG[3]
  PIN S2BEG[4]
    DIRECTION OUTPUT ;
    USE SIGNAL ;
    ANTENNADIFFAREA 0.702900 ;
    PORT
      LAYER met2 ;
        RECT 106.350 0.000 106.630 0.280 ;
    END
  END S2BEG[4]
  PIN S2BEG[5]
    DIRECTION OUTPUT ;
    USE SIGNAL ;
    ANTENNADIFFAREA 0.702900 ;
    PORT
      LAYER met2 ;
        RECT 107.730 0.000 108.010 0.280 ;
    END
  END S2BEG[5]
  PIN S2BEG[6]
    DIRECTION OUTPUT ;
    USE SIGNAL ;
    ANTENNADIFFAREA 0.702900 ;
    PORT
      LAYER met2 ;
        RECT 109.110 0.000 109.390 0.280 ;
    END
  END S2BEG[6]
  PIN S2BEG[7]
    DIRECTION OUTPUT ;
    USE SIGNAL ;
    ANTENNADIFFAREA 0.702900 ;
    PORT
      LAYER met2 ;
        RECT 110.490 0.000 110.770 0.280 ;
    END
  END S2BEG[7]
  PIN S2BEGb[0]
    DIRECTION OUTPUT ;
    USE SIGNAL ;
    ANTENNADIFFAREA 0.702900 ;
    PORT
      LAYER met2 ;
        RECT 111.870 0.000 112.150 0.280 ;
    END
  END S2BEGb[0]
  PIN S2BEGb[1]
    DIRECTION OUTPUT ;
    USE SIGNAL ;
    ANTENNADIFFAREA 0.702900 ;
    PORT
      LAYER met2 ;
        RECT 113.250 0.000 113.530 0.280 ;
    END
  END S2BEGb[1]
  PIN S2BEGb[2]
    DIRECTION OUTPUT ;
    USE SIGNAL ;
    ANTENNADIFFAREA 0.702900 ;
    PORT
      LAYER met2 ;
        RECT 114.630 0.000 114.910 0.280 ;
    END
  END S2BEGb[2]
  PIN S2BEGb[3]
    DIRECTION OUTPUT ;
    USE SIGNAL ;
    ANTENNADIFFAREA 0.702900 ;
    PORT
      LAYER met2 ;
        RECT 116.010 0.000 116.290 0.280 ;
    END
  END S2BEGb[3]
  PIN S2BEGb[4]
    DIRECTION OUTPUT ;
    USE SIGNAL ;
    ANTENNADIFFAREA 0.702900 ;
    PORT
      LAYER met2 ;
        RECT 117.390 0.000 117.670 0.280 ;
    END
  END S2BEGb[4]
  PIN S2BEGb[5]
    DIRECTION OUTPUT ;
    USE SIGNAL ;
    ANTENNADIFFAREA 0.702900 ;
    PORT
      LAYER met2 ;
        RECT 118.770 0.000 119.050 0.280 ;
    END
  END S2BEGb[5]
  PIN S2BEGb[6]
    DIRECTION OUTPUT ;
    USE SIGNAL ;
    ANTENNADIFFAREA 0.702900 ;
    PORT
      LAYER met2 ;
        RECT 120.150 0.000 120.430 0.280 ;
    END
  END S2BEGb[6]
  PIN S2BEGb[7]
    DIRECTION OUTPUT ;
    USE SIGNAL ;
    ANTENNADIFFAREA 0.702900 ;
    PORT
      LAYER met2 ;
        RECT 121.530 0.000 121.810 0.280 ;
    END
  END S2BEGb[7]
  PIN S4BEG[0]
    DIRECTION OUTPUT ;
    USE SIGNAL ;
    ANTENNADIFFAREA 0.702900 ;
    PORT
      LAYER met2 ;
        RECT 122.910 0.000 123.190 0.280 ;
    END
  END S4BEG[0]
  PIN S4BEG[10]
    DIRECTION OUTPUT ;
    USE SIGNAL ;
    ANTENNADIFFAREA 0.702900 ;
    PORT
      LAYER met2 ;
        RECT 136.710 0.000 136.990 0.280 ;
    END
  END S4BEG[10]
  PIN S4BEG[11]
    DIRECTION OUTPUT ;
    USE SIGNAL ;
    ANTENNADIFFAREA 0.702900 ;
    PORT
      LAYER met2 ;
        RECT 138.090 0.000 138.370 0.280 ;
    END
  END S4BEG[11]
  PIN S4BEG[12]
    DIRECTION OUTPUT ;
    USE SIGNAL ;
    ANTENNADIFFAREA 0.702900 ;
    PORT
      LAYER met2 ;
        RECT 139.470 0.000 139.750 0.280 ;
    END
  END S4BEG[12]
  PIN S4BEG[13]
    DIRECTION OUTPUT ;
    USE SIGNAL ;
    ANTENNADIFFAREA 0.702900 ;
    PORT
      LAYER met2 ;
        RECT 140.850 0.000 141.130 0.280 ;
    END
  END S4BEG[13]
  PIN S4BEG[14]
    DIRECTION OUTPUT ;
    USE SIGNAL ;
    ANTENNADIFFAREA 0.702900 ;
    PORT
      LAYER met2 ;
        RECT 142.230 0.000 142.510 0.280 ;
    END
  END S4BEG[14]
  PIN S4BEG[15]
    DIRECTION OUTPUT ;
    USE SIGNAL ;
    ANTENNADIFFAREA 0.702900 ;
    PORT
      LAYER met2 ;
        RECT 143.610 0.000 143.890 0.280 ;
    END
  END S4BEG[15]
  PIN S4BEG[1]
    DIRECTION OUTPUT ;
    USE SIGNAL ;
    ANTENNADIFFAREA 0.702900 ;
    PORT
      LAYER met2 ;
        RECT 124.290 0.000 124.570 0.280 ;
    END
  END S4BEG[1]
  PIN S4BEG[2]
    DIRECTION OUTPUT ;
    USE SIGNAL ;
    ANTENNADIFFAREA 0.702900 ;
    PORT
      LAYER met2 ;
        RECT 125.670 0.000 125.950 0.280 ;
    END
  END S4BEG[2]
  PIN S4BEG[3]
    DIRECTION OUTPUT ;
    USE SIGNAL ;
    ANTENNADIFFAREA 0.702900 ;
    PORT
      LAYER met2 ;
        RECT 127.050 0.000 127.330 0.280 ;
    END
  END S4BEG[3]
  PIN S4BEG[4]
    DIRECTION OUTPUT ;
    USE SIGNAL ;
    ANTENNADIFFAREA 0.702900 ;
    PORT
      LAYER met2 ;
        RECT 128.430 0.000 128.710 0.280 ;
    END
  END S4BEG[4]
  PIN S4BEG[5]
    DIRECTION OUTPUT ;
    USE SIGNAL ;
    ANTENNADIFFAREA 0.702900 ;
    PORT
      LAYER met2 ;
        RECT 129.810 0.000 130.090 0.280 ;
    END
  END S4BEG[5]
  PIN S4BEG[6]
    DIRECTION OUTPUT ;
    USE SIGNAL ;
    ANTENNADIFFAREA 0.702900 ;
    PORT
      LAYER met2 ;
        RECT 131.190 0.000 131.470 0.280 ;
    END
  END S4BEG[6]
  PIN S4BEG[7]
    DIRECTION OUTPUT ;
    USE SIGNAL ;
    ANTENNADIFFAREA 0.702900 ;
    PORT
      LAYER met2 ;
        RECT 132.570 0.000 132.850 0.280 ;
    END
  END S4BEG[7]
  PIN S4BEG[8]
    DIRECTION OUTPUT ;
    USE SIGNAL ;
    ANTENNADIFFAREA 0.702900 ;
    PORT
      LAYER met2 ;
        RECT 133.950 0.000 134.230 0.280 ;
    END
  END S4BEG[8]
  PIN S4BEG[9]
    DIRECTION OUTPUT ;
    USE SIGNAL ;
    ANTENNADIFFAREA 0.702900 ;
    PORT
      LAYER met2 ;
        RECT 135.330 0.000 135.610 0.280 ;
    END
  END S4BEG[9]
  PIN SS4BEG[0]
    DIRECTION OUTPUT ;
    USE SIGNAL ;
    ANTENNADIFFAREA 0.702900 ;
    PORT
      LAYER met2 ;
        RECT 144.990 0.000 145.270 0.280 ;
    END
  END SS4BEG[0]
  PIN SS4BEG[10]
    DIRECTION OUTPUT ;
    USE SIGNAL ;
    ANTENNADIFFAREA 0.702900 ;
    PORT
      LAYER met2 ;
        RECT 158.790 0.000 159.070 0.280 ;
    END
  END SS4BEG[10]
  PIN SS4BEG[11]
    DIRECTION OUTPUT ;
    USE SIGNAL ;
    ANTENNADIFFAREA 0.702900 ;
    PORT
      LAYER met2 ;
        RECT 160.170 0.000 160.450 0.280 ;
    END
  END SS4BEG[11]
  PIN SS4BEG[12]
    DIRECTION OUTPUT ;
    USE SIGNAL ;
    ANTENNADIFFAREA 0.702900 ;
    PORT
      LAYER met2 ;
        RECT 161.550 0.000 161.830 0.280 ;
    END
  END SS4BEG[12]
  PIN SS4BEG[13]
    DIRECTION OUTPUT ;
    USE SIGNAL ;
    ANTENNADIFFAREA 0.702900 ;
    PORT
      LAYER met2 ;
        RECT 162.930 0.000 163.210 0.280 ;
    END
  END SS4BEG[13]
  PIN SS4BEG[14]
    DIRECTION OUTPUT ;
    USE SIGNAL ;
    ANTENNADIFFAREA 0.702900 ;
    PORT
      LAYER met2 ;
        RECT 164.310 0.000 164.590 0.280 ;
    END
  END SS4BEG[14]
  PIN SS4BEG[15]
    DIRECTION OUTPUT ;
    USE SIGNAL ;
    ANTENNADIFFAREA 0.702900 ;
    PORT
      LAYER met2 ;
        RECT 165.690 0.000 165.970 0.280 ;
    END
  END SS4BEG[15]
  PIN SS4BEG[1]
    DIRECTION OUTPUT ;
    USE SIGNAL ;
    ANTENNADIFFAREA 0.702900 ;
    PORT
      LAYER met2 ;
        RECT 146.370 0.000 146.650 0.280 ;
    END
  END SS4BEG[1]
  PIN SS4BEG[2]
    DIRECTION OUTPUT ;
    USE SIGNAL ;
    ANTENNADIFFAREA 0.702900 ;
    PORT
      LAYER met2 ;
        RECT 147.750 0.000 148.030 0.280 ;
    END
  END SS4BEG[2]
  PIN SS4BEG[3]
    DIRECTION OUTPUT ;
    USE SIGNAL ;
    ANTENNADIFFAREA 0.702900 ;
    PORT
      LAYER met2 ;
        RECT 149.130 0.000 149.410 0.280 ;
    END
  END SS4BEG[3]
  PIN SS4BEG[4]
    DIRECTION OUTPUT ;
    USE SIGNAL ;
    ANTENNADIFFAREA 0.702900 ;
    PORT
      LAYER met2 ;
        RECT 150.510 0.000 150.790 0.280 ;
    END
  END SS4BEG[4]
  PIN SS4BEG[5]
    DIRECTION OUTPUT ;
    USE SIGNAL ;
    ANTENNADIFFAREA 0.702900 ;
    PORT
      LAYER met2 ;
        RECT 151.890 0.000 152.170 0.280 ;
    END
  END SS4BEG[5]
  PIN SS4BEG[6]
    DIRECTION OUTPUT ;
    USE SIGNAL ;
    ANTENNADIFFAREA 0.702900 ;
    PORT
      LAYER met2 ;
        RECT 153.270 0.000 153.550 0.280 ;
    END
  END SS4BEG[6]
  PIN SS4BEG[7]
    DIRECTION OUTPUT ;
    USE SIGNAL ;
    ANTENNADIFFAREA 0.702900 ;
    PORT
      LAYER met2 ;
        RECT 154.650 0.000 154.930 0.280 ;
    END
  END SS4BEG[7]
  PIN SS4BEG[8]
    DIRECTION OUTPUT ;
    USE SIGNAL ;
    ANTENNADIFFAREA 0.702900 ;
    PORT
      LAYER met2 ;
        RECT 156.030 0.000 156.310 0.280 ;
    END
  END SS4BEG[8]
  PIN SS4BEG[9]
    DIRECTION OUTPUT ;
    USE SIGNAL ;
    ANTENNADIFFAREA 0.702900 ;
    PORT
      LAYER met2 ;
        RECT 157.410 0.000 157.690 0.280 ;
    END
  END SS4BEG[9]
  PIN VGND
    DIRECTION INOUT ;
    USE GROUND ;
    PORT
      LAYER met4 ;
        RECT 12.260 0.000 13.860 57.120 ;
    END
    PORT
      LAYER met4 ;
        RECT 42.260 0.000 43.860 57.120 ;
    END
    PORT
      LAYER met4 ;
        RECT 72.260 0.000 73.860 57.120 ;
    END
    PORT
      LAYER met4 ;
        RECT 102.260 0.000 103.860 57.120 ;
    END
    PORT
      LAYER met4 ;
        RECT 132.260 0.000 133.860 57.120 ;
    END
    PORT
      LAYER met4 ;
        RECT 162.260 0.000 163.860 57.120 ;
    END
    PORT
      LAYER met4 ;
        RECT 192.260 0.000 193.860 57.120 ;
    END
  END VGND
  PIN VPWR
    DIRECTION INOUT ;
    USE POWER ;
    PORT
      LAYER met4 ;
        RECT 6.960 0.000 8.560 57.120 ;
    END
    PORT
      LAYER met4 ;
        RECT 36.960 0.000 38.560 57.120 ;
    END
    PORT
      LAYER met4 ;
        RECT 66.960 0.000 68.560 57.120 ;
    END
    PORT
      LAYER met4 ;
        RECT 96.960 0.000 98.560 57.120 ;
    END
    PORT
      LAYER met4 ;
        RECT 126.960 0.000 128.560 57.120 ;
    END
    PORT
      LAYER met4 ;
        RECT 156.960 0.000 158.560 57.120 ;
    END
    PORT
      LAYER met4 ;
        RECT 186.960 0.000 188.560 57.120 ;
    END
  END VPWR
  OBS
      LAYER nwell ;
        RECT 2.570 2.635 208.110 54.590 ;
      LAYER li1 ;
        RECT 2.760 2.635 207.920 54.485 ;
      LAYER met1 ;
        RECT 2.760 0.380 207.920 54.640 ;
      LAYER met2 ;
        RECT 3.310 56.560 8.550 56.840 ;
        RECT 9.390 56.560 18.670 56.840 ;
        RECT 19.510 56.560 28.790 56.840 ;
        RECT 29.630 56.560 38.910 56.840 ;
        RECT 39.750 56.560 49.030 56.840 ;
        RECT 49.870 56.560 59.150 56.840 ;
        RECT 59.990 56.560 69.270 56.840 ;
        RECT 70.110 56.560 79.390 56.840 ;
        RECT 80.230 56.560 89.510 56.840 ;
        RECT 90.350 56.560 99.630 56.840 ;
        RECT 100.470 56.560 109.750 56.840 ;
        RECT 110.590 56.560 119.870 56.840 ;
        RECT 120.710 56.560 129.990 56.840 ;
        RECT 130.830 56.560 140.110 56.840 ;
        RECT 140.950 56.560 150.230 56.840 ;
        RECT 151.070 56.560 160.350 56.840 ;
        RECT 161.190 56.560 170.470 56.840 ;
        RECT 171.310 56.560 180.590 56.840 ;
        RECT 181.430 56.560 190.710 56.840 ;
        RECT 191.550 56.560 200.830 56.840 ;
        RECT 3.310 0.560 201.380 56.560 ;
        RECT 3.310 0.270 16.370 0.560 ;
        RECT 17.210 0.270 17.750 0.560 ;
        RECT 18.590 0.270 19.130 0.560 ;
        RECT 19.970 0.270 20.510 0.560 ;
        RECT 21.350 0.270 21.890 0.560 ;
        RECT 22.730 0.270 23.270 0.560 ;
        RECT 24.110 0.270 24.650 0.560 ;
        RECT 25.490 0.270 26.030 0.560 ;
        RECT 26.870 0.270 27.410 0.560 ;
        RECT 28.250 0.270 28.790 0.560 ;
        RECT 29.630 0.270 30.170 0.560 ;
        RECT 31.010 0.270 31.550 0.560 ;
        RECT 32.390 0.270 32.930 0.560 ;
        RECT 33.770 0.270 34.310 0.560 ;
        RECT 35.150 0.270 35.690 0.560 ;
        RECT 36.530 0.270 37.070 0.560 ;
        RECT 37.910 0.270 38.450 0.560 ;
        RECT 39.290 0.270 39.830 0.560 ;
        RECT 40.670 0.270 41.210 0.560 ;
        RECT 42.050 0.270 42.590 0.560 ;
        RECT 43.430 0.270 43.970 0.560 ;
        RECT 44.810 0.270 45.350 0.560 ;
        RECT 46.190 0.270 46.730 0.560 ;
        RECT 47.570 0.270 48.110 0.560 ;
        RECT 48.950 0.270 49.490 0.560 ;
        RECT 50.330 0.270 50.870 0.560 ;
        RECT 51.710 0.270 52.250 0.560 ;
        RECT 53.090 0.270 53.630 0.560 ;
        RECT 54.470 0.270 55.010 0.560 ;
        RECT 55.850 0.270 56.390 0.560 ;
        RECT 57.230 0.270 57.770 0.560 ;
        RECT 58.610 0.270 59.150 0.560 ;
        RECT 59.990 0.270 60.530 0.560 ;
        RECT 61.370 0.270 61.910 0.560 ;
        RECT 62.750 0.270 63.290 0.560 ;
        RECT 64.130 0.270 64.670 0.560 ;
        RECT 65.510 0.270 66.050 0.560 ;
        RECT 66.890 0.270 67.430 0.560 ;
        RECT 68.270 0.270 68.810 0.560 ;
        RECT 69.650 0.270 70.190 0.560 ;
        RECT 71.030 0.270 71.570 0.560 ;
        RECT 72.410 0.270 72.950 0.560 ;
        RECT 73.790 0.270 74.330 0.560 ;
        RECT 75.170 0.270 75.710 0.560 ;
        RECT 76.550 0.270 77.090 0.560 ;
        RECT 77.930 0.270 78.470 0.560 ;
        RECT 79.310 0.270 79.850 0.560 ;
        RECT 80.690 0.270 81.230 0.560 ;
        RECT 82.070 0.270 82.610 0.560 ;
        RECT 83.450 0.270 83.990 0.560 ;
        RECT 84.830 0.270 85.370 0.560 ;
        RECT 86.210 0.270 86.750 0.560 ;
        RECT 87.590 0.270 88.130 0.560 ;
        RECT 88.970 0.270 89.510 0.560 ;
        RECT 90.350 0.270 90.890 0.560 ;
        RECT 91.730 0.270 92.270 0.560 ;
        RECT 93.110 0.270 93.650 0.560 ;
        RECT 94.490 0.270 95.030 0.560 ;
        RECT 95.870 0.270 96.410 0.560 ;
        RECT 97.250 0.270 97.790 0.560 ;
        RECT 98.630 0.270 99.170 0.560 ;
        RECT 100.010 0.270 100.550 0.560 ;
        RECT 101.390 0.270 101.930 0.560 ;
        RECT 102.770 0.270 103.310 0.560 ;
        RECT 104.150 0.270 104.690 0.560 ;
        RECT 105.530 0.270 106.070 0.560 ;
        RECT 106.910 0.270 107.450 0.560 ;
        RECT 108.290 0.270 108.830 0.560 ;
        RECT 109.670 0.270 110.210 0.560 ;
        RECT 111.050 0.270 111.590 0.560 ;
        RECT 112.430 0.270 112.970 0.560 ;
        RECT 113.810 0.270 114.350 0.560 ;
        RECT 115.190 0.270 115.730 0.560 ;
        RECT 116.570 0.270 117.110 0.560 ;
        RECT 117.950 0.270 118.490 0.560 ;
        RECT 119.330 0.270 119.870 0.560 ;
        RECT 120.710 0.270 121.250 0.560 ;
        RECT 122.090 0.270 122.630 0.560 ;
        RECT 123.470 0.270 124.010 0.560 ;
        RECT 124.850 0.270 125.390 0.560 ;
        RECT 126.230 0.270 126.770 0.560 ;
        RECT 127.610 0.270 128.150 0.560 ;
        RECT 128.990 0.270 129.530 0.560 ;
        RECT 130.370 0.270 130.910 0.560 ;
        RECT 131.750 0.270 132.290 0.560 ;
        RECT 133.130 0.270 133.670 0.560 ;
        RECT 134.510 0.270 135.050 0.560 ;
        RECT 135.890 0.270 136.430 0.560 ;
        RECT 137.270 0.270 137.810 0.560 ;
        RECT 138.650 0.270 139.190 0.560 ;
        RECT 140.030 0.270 140.570 0.560 ;
        RECT 141.410 0.270 141.950 0.560 ;
        RECT 142.790 0.270 143.330 0.560 ;
        RECT 144.170 0.270 144.710 0.560 ;
        RECT 145.550 0.270 146.090 0.560 ;
        RECT 146.930 0.270 147.470 0.560 ;
        RECT 148.310 0.270 148.850 0.560 ;
        RECT 149.690 0.270 150.230 0.560 ;
        RECT 151.070 0.270 151.610 0.560 ;
        RECT 152.450 0.270 152.990 0.560 ;
        RECT 153.830 0.270 154.370 0.560 ;
        RECT 155.210 0.270 155.750 0.560 ;
        RECT 156.590 0.270 157.130 0.560 ;
        RECT 157.970 0.270 158.510 0.560 ;
        RECT 159.350 0.270 159.890 0.560 ;
        RECT 160.730 0.270 161.270 0.560 ;
        RECT 162.110 0.270 162.650 0.560 ;
        RECT 163.490 0.270 164.030 0.560 ;
        RECT 164.870 0.270 165.410 0.560 ;
        RECT 166.250 0.270 166.790 0.560 ;
        RECT 167.630 0.270 168.170 0.560 ;
        RECT 169.010 0.270 169.550 0.560 ;
        RECT 170.390 0.270 170.930 0.560 ;
        RECT 171.770 0.270 172.310 0.560 ;
        RECT 173.150 0.270 173.690 0.560 ;
        RECT 174.530 0.270 175.070 0.560 ;
        RECT 175.910 0.270 176.450 0.560 ;
        RECT 177.290 0.270 177.830 0.560 ;
        RECT 178.670 0.270 179.210 0.560 ;
        RECT 180.050 0.270 180.590 0.560 ;
        RECT 181.430 0.270 181.970 0.560 ;
        RECT 182.810 0.270 183.350 0.560 ;
        RECT 184.190 0.270 184.730 0.560 ;
        RECT 185.570 0.270 186.110 0.560 ;
        RECT 186.950 0.270 187.490 0.560 ;
        RECT 188.330 0.270 188.870 0.560 ;
        RECT 189.710 0.270 190.250 0.560 ;
        RECT 191.090 0.270 191.630 0.560 ;
        RECT 192.470 0.270 193.010 0.560 ;
        RECT 193.850 0.270 201.380 0.560 ;
      LAYER met3 ;
        RECT 0.600 50.000 210.080 54.565 ;
        RECT 1.000 6.440 209.680 50.000 ;
        RECT 0.600 0.855 210.080 6.440 ;
  END
END N_term_single
END LIBRARY

